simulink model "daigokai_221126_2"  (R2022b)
settings: Solver=FixedStepDiscrete  StartTime=0.0  StopTime=40  FixedStep=1e-3  RelTol=1e-3
PreLoadFcn:
  | Kp=1
  | Ki=1

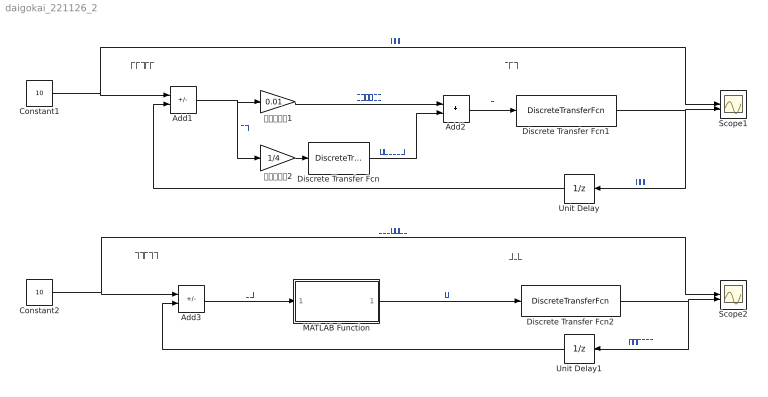
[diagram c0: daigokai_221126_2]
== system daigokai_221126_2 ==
  note: プログラム
  note: プログラム
  note: 乗り物
  note: 乗り物
  Add1 : Sum  Inputs=+-
  Add2 : Sum
  Add3 : Sum  Inputs=+-
  Constant1 : Constant  Value=10
  Constant2 : Constant  Value=10
  Discrete Transfer Fcn : DiscreteTransferFcn  Numerator=[0.001 0]  Denominator=[1 -1]
  Discrete Transfer Fcn1 : DiscreteTransferFcn  Numerator=[0.001 0]  Denominator=[(1+1*0.001) -1]
  Discrete Transfer Fcn2 : DiscreteTransferFcn  Numerator=[0.001 0]  Denominator=[(1+1*0.001) -1]
  MATLAB Function : MATLAB Function  TreatAsAtomicUnit=on
  Scope1 : Scope  NumInputPorts=2
  Scope2 : Scope  NumInputPorts=2
  Unit Delay : UnitDelay  SampleTime=-1  HasFrameUpgradeWarning=on
  Unit Delay1 : UnitDelay  SampleTime=-1  HasFrameUpgradeWarning=on
  比例ゲイン1 : Gain  Gain=0.01
  比例ゲイン2 : Gain  Gain=1/4
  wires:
  Discrete Transfer Fcn1/1 -> Unit Delay/1, Scope1/2  "乗り物の速度"
  Add1/1 -> 比例ゲイン2/1, 比例ゲイン1/1  "偏差"
  比例ゲイン1/1 -> Add2/1  "比例項の出力"
  Constant1/1 -> Scope1/1, Add1/1  "ロボットの速度"
  比例ゲイン2/1 -> Discrete Transfer Fcn/1
  Add2/1 -> Discrete Transfer Fcn1/1  "力"
  Discrete Transfer Fcn/1 -> Add2/2  "積分項の出力"
  Add3/1 -> MATLAB Function/1(hensa)  "偏差"
  Unit Delay/1 -> Add1/2
  MATLAB Function/1(chikara) -> Discrete Transfer Fcn2/1  "力"
  Discrete Transfer Fcn2/1 -> Unit Delay1/1, Scope2/2  "乗り物の速度"
  Unit Delay1/1 -> Add3/2
  Constant2/1 -> Scope2/1, Add3/1  "ロボットの速度"

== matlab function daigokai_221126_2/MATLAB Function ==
function chikara = fcn(hensa)
    persistent sekibun_kou
    if isempty(sekibun_kou)
        sekibun_kou = 0;
    end
    hirei_kou = 0.01*hensa;
    sekibun_kou = sekibun_kou+1/4*hensa*0.001;
    chikara = hirei_kou + sekibun_kou;
end
